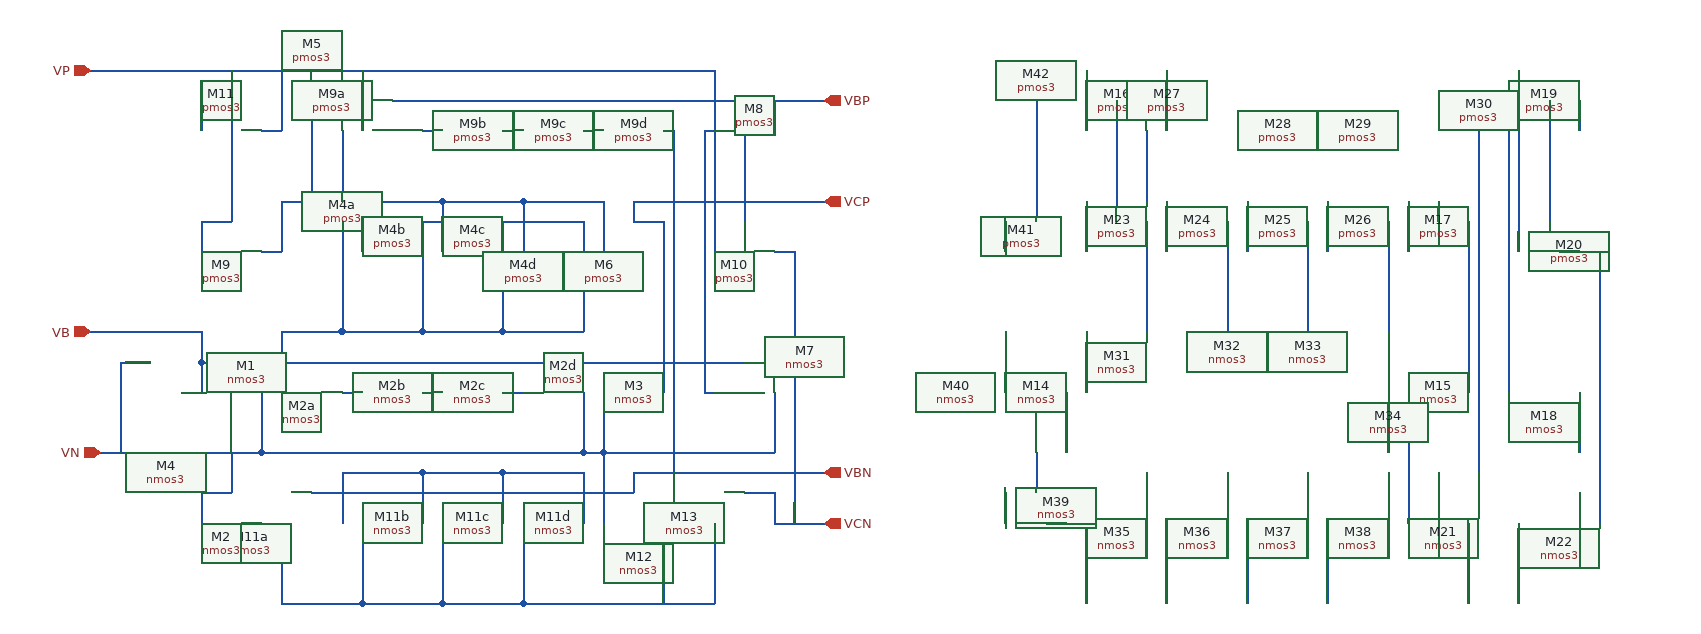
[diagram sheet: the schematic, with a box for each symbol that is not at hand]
v {xschem version=3.4.3 file_version=1.2
}
G {}
K {}
V {}
S {}
E {}
N -10 -220 -10 -170 {
lab=#net1}
N -10 -220 70 -220 {
lab=#net1}
N 70 -220 70 -170 {
lab=#net1}
N 70 -220 150 -220 {
lab=#net1}
N 150 -220 150 -170 {
lab=#net1}
N 150 -220 230 -220 {
lab=#net1}
N 230 -220 230 -170 {
lab=#net1}
N 50 -170 50 -90 {
lab=#net2}
N 50 -90 130 -90 {
lab=#net2}
N 130 -170 130 -90 {
lab=#net2}
N 130 -90 210 -90 {
lab=#net2}
N 210 -170 210 -90 {
lab=#net2}
N 210 -90 290 -90 {
lab=#net2}
N 290 -170 290 -90 {
lab=#net2}
N 20 -200 260 -200 {
lab=#net2}
N 130 -290 150 -290 {
lab=#net3}
N 210 -290 230 -290 {
lab=#net4}
N 290 -290 310 -290 {
lab=#net5}
N 100 -320 340 -320 {
lab=VBP}
N -10 -350 -10 -290 {
lab=VP}
N 20 -320 20 -200 {
lab=#net2}
N 50 -290 50 -220 {
lab=#net1}
N 310 -220 310 -170 {
lab=#net1}
N 230 -220 310 -220 {
lab=#net1}
N 50 -30 70 -30 {
lab=#net6}
N 130 -30 150 -30 {
lab=#net7}
N 210 -30 230 -30 {
lab=#net8}
N 20 -60 260 -60 {
lab=VB}
N 20 70 260 70 {
lab=VBN}
N 50 50 50 100 {
lab=#net9}
N 50 50 130 50 {
lab=#net9}
N 130 50 130 100 {
lab=#net9}
N 130 50 210 50 {
lab=#net9}
N 210 50 210 100 {
lab=#net9}
N 210 50 290 50 {
lab=#net9}
N 290 50 290 100 {
lab=#net9}
N -10 100 -10 180 {
lab=#net10}
N -10 180 70 180 {
lab=#net10}
N 70 100 70 180 {
lab=#net10}
N 70 180 150 180 {
lab=#net10}
N 150 100 150 180 {
lab=#net10}
N 150 180 230 180 {
lab=#net10}
N 230 100 230 180 {
lab=#net10}
N -90 -60 -90 -30 {
lab=VB}
N -90 -60 -60 -60 {
lab=VB}
N -60 -60 20 -60 {
lab=VB}
N 260 -60 340 -60 {
lab=VB}
N 340 -200 370 -200 {
lab=VCP}
N 370 -200 370 -170 {
lab=VCP}
N 340 -220 340 -200 {
lab=VCP}
N 340 -220 500 -220 {
lab=VCP}
N 370 -170 370 -30 {
lab=VCP}
N -10 -90 -10 -30 {
lab=#net2}
N -10 -90 50 -90 {
lab=#net2}
N 230 180 390 180 {
lab=#net10}
N 420 100 420 180 {
lab=#net10}
N -30 -30 -30 30 {
lab=VN}
N -190 30 -30 30 {
lab=VN}
N 290 -30 290 30 {
lab=VN}
N -30 30 290 30 {
lab=VN}
N 290 30 310 30 {
lab=VN}
N 310 -30 310 30 {
lab=VN}
N 310 30 390 30 {
lab=VN}
N 310 30 310 100 {
lab=VN}
N 370 100 370 180 {
lab=#net10}
N 450 70 480 70 {
lab=VCN}
N 480 70 480 100 {
lab=VCN}
N 480 100 530 100 {
lab=VCN}
N 260 70 340 70 {
lab=VBN}
N 340 50 340 70 {
lab=VBN}
N 370 -290 380 -290 {
lab=VBN}
N 380 -290 380 50 {
lab=VBN}
N 50 -200 50 -170 {
lab=#net2}
N 130 -200 130 -170 {
lab=#net2}
N 210 -200 210 -170 {
lab=#net2}
N 260 -200 290 -200 {
lab=#net2}
N 290 -200 290 -170 {
lab=#net2}
N 450 -320 450 -200 {
lab=VBP}
N 340 -320 390 -320 {
lab=VBP}
N 70 -350 70 -290 {
lab=VP}
N 420 30 480 30 {
lab=VN}
N 480 -30 480 30 {
lab=VN}
N 390 30 420 30 {
lab=VN}
N 500 -220 530 -220 {
lab=VCP}
N 450 -320 530 -320 {
lab=VBP}
N 410 -290 420 -290 {
lab=VP}
N 410 -290 410 -30 {
lab=VP}
N 410 -30 420 -30 {
lab=VP}
N 390 180 420 180 {
lab=#net10}
N 480 -320 480 -290 {
lab=VBP}
N 420 -350 420 -170 {
lab=VP}
N 390 -320 450 -320 {
lab=VBP}
N -50 -350 420 -350 {
lab=VP}
N 480 -170 500 -170 {
lab=VCN}
N 500 -170 500 100 {
lab=VCN}
N 340 50 530 50 {
lab=VBN}
N 340 -60 450 -60 {
lab=VB}
N -90 70 -90 100 {
lab=VN}
N -90 70 -60 70 {
lab=VN}
N -30 100 -10 100 {
lab=#net10}
N -60 30 -60 70 {
lab=VN}
N -110 -30 -90 -30 {
lab=VB}
N -170 -60 -140 -60 {
lab=VN}
N -170 -60 -170 -30 {
lab=VN}
N -170 -30 -170 30 {
lab=VN}
N -200 -90 -90 -90 {
lab=VB}
N -90 -90 -90 -60 {
lab=VB}
N -90 -200 -90 -170 {
lab=VP}
N -90 -200 -60 -200 {
lab=VP}
N -30 -170 -10 -170 {
lab=#net1}
N -200 -350 -50 -350 {
lab=VP}
N -30 -290 -10 -290 {}
N -90 -320 -90 -290 {}
N -90 -320 -60 -320 {}
N -60 -350 -60 -320 {}
N -60 -320 -60 -200 {}
N 790 -220 790 -170 {
lab=#net1}
N 870 -220 870 -170 {
lab=#net1}
N 950 -220 950 -170 {
lab=#net1}
N 1030 -220 1030 -170 {
lab=#net1}
N 850 -170 850 -90 {
lab=#net2}
N 930 -170 930 -90 {
lab=#net2}
N 1010 -170 1010 -90 {
lab=#net2}
N 1090 -170 1090 -90 {
lab=#net2}
N 790 -350 790 -290 {
lab=VP}
N 820 -320 820 -200 {
lab=#net2}
N 850 -290 850 -220 {
lab=#net1}
N 1110 -220 1110 -170 {
lab=#net1}
N 850 50 850 100 {
lab=#net9}
N 930 50 930 100 {
lab=#net9}
N 1010 50 1010 100 {
lab=#net9}
N 1090 50 1090 100 {
lab=#net9}
N 790 100 790 180 {
lab=#net10}
N 870 100 870 180 {
lab=#net10}
N 950 100 950 180 {
lab=#net10}
N 1030 100 1030 180 {
lab=#net10}
N 710 -60 710 -30 {
lab=VB}
N 1170 -200 1170 -170 {
lab=VCP}
N 1140 -220 1140 -200 {
lab=VCP}
N 1170 -170 1170 -30 {
lab=VCP}
N 790 -90 790 -30 {
lab=#net2}
N 1220 100 1220 180 {
lab=#net10}
N 770 -30 770 30 {
lab=VN}
N 1090 -30 1090 30 {
lab=VN}
N 1110 -30 1110 30 {
lab=VN}
N 1110 30 1110 100 {
lab=VN}
N 1170 100 1170 180 {
lab=#net10}
N 1280 70 1280 100 {
lab=VCN}
N 1140 50 1140 70 {
lab=VBN}
N 1180 -290 1180 50 {
lab=VBN}
N 850 -200 850 -170 {
lab=#net2}
N 930 -200 930 -170 {
lab=#net2}
N 1010 -200 1010 -170 {
lab=#net2}
N 1090 -200 1090 -170 {
lab=#net2}
N 1250 -320 1250 -200 {
lab=VBP}
N 870 -350 870 -290 {
lab=VP}
N 1280 -30 1280 30 {
lab=VN}
N 1210 -290 1210 -30 {
lab=VP}
N 1280 -320 1280 -290 {
lab=VBP}
N 1220 -350 1220 -170 {
lab=VP}
N 1260 -170 1280 -170 {
lab=VCN}
N 1300 -170 1300 100 {
lab=VCN}
N 710 70 710 100 {
lab=VN}
N 750 100 770 100 {
lab=#net10}
N 740 30 740 70 {
lab=VN}
N 710 -90 710 -60 {
lab=VB}
N 710 -200 710 -170 {
lab=VP}
N 740 -320 740 -200 {}
C {madvlsi/nmos3.sym} -60 -30 3 1 {name=M1
L=0.5
W=12
body=VN
nf=1
mult=1
ad="'int((nf+1)/2) * W/nf * 0.29'" 
pd="'2*int((nf+1)/2) * (W/nf + 0.29)'"
as="'int((nf+2)/2) * W/nf * 0.29'" 
ps="'2*int((nf+2)/2) * (W/nf + 0.29)'"
nrd="'0.29 / W'" nrs="'0.29 / W'"
sa=0 sb=0 sd=0
model=nfet_01v8
spiceprefix=X
}
C {madvlsi/nmos3.sym} 340 -30 1 0 {name=M3
L=0.5
W=12
body=VN
nf=1
mult=1
ad="'int((nf+1)/2) * W/nf * 0.29'" 
pd="'2*int((nf+1)/2) * (W/nf + 0.29)'"
as="'int((nf+2)/2) * W/nf * 0.29'" 
ps="'2*int((nf+2)/2) * (W/nf + 0.29)'"
nrd="'0.29 / W'" nrs="'0.29 / W'"
sa=0 sb=0 sd=0
model=nfet_01v8
spiceprefix=X
}
C {madvlsi/pmos3.sym} 20 -290 3 1 {name=M5
L=0.5
W=12
body=VP
nf=1
mult=1
ad="'int((nf+1)/2) * W/nf * 0.29'" 
pd="'2*int((nf+1)/2) * (W/nf + 0.29)'"
as="'int((nf+2)/2) * W/nf * 0.29'" 
ps="'2*int((nf+2)/2) * (W/nf + 0.29)'"
nrd="'0.29 / W'" nrs="'0.29 / W'"
sa=0 sb=0 sd=0
model=pfet_01v8
spiceprefix=X
}
C {madvlsi/pmos3.sym} 340 -170 3 1 {name=M6
L=0.5
W=12
body=VP
nf=1
mult=1
ad="'int((nf+1)/2) * W/nf * 0.29'" 
pd="'2*int((nf+1)/2) * (W/nf + 0.29)'"
as="'int((nf+2)/2) * W/nf * 0.29'" 
ps="'2*int((nf+2)/2) * (W/nf + 0.29)'"
nrd="'0.29 / W'" nrs="'0.29 / W'"
sa=0 sb=0 sd=0
model=pfet_01v8
spiceprefix=X
}
C {madvlsi/nmos3.sym} 450 -30 3 1 {name=M7
L=0.5
W=12
body=VN
nf=1
mult=1
ad="'int((nf+1)/2) * W/nf * 0.29'" 
pd="'2*int((nf+1)/2) * (W/nf + 0.29)'"
as="'int((nf+2)/2) * W/nf * 0.29'" 
ps="'2*int((nf+2)/2) * (W/nf + 0.29)'"
nrd="'0.29 / W'" nrs="'0.29 / W'"
sa=0 sb=0 sd=0
model=nfet_01v8
spiceprefix=X
}
C {madvlsi/pmos3.sym} 450 -290 3 1 {name=M8
L=0.5
W=12
body=VP
nf=1
mult=1
ad="'int((nf+1)/2) * W/nf * 0.29'" 
pd="'2*int((nf+1)/2) * (W/nf + 0.29)'"
as="'int((nf+2)/2) * W/nf * 0.29'" 
ps="'2*int((nf+2)/2) * (W/nf + 0.29)'"
nrd="'0.29 / W'" nrs="'0.29 / W'"
sa=0 sb=0 sd=0
model=pfet_01v8
spiceprefix=X
}
C {madvlsi/pmos3.sym} 450 -170 3 1 {name=M10
L=0.5
W=12
body=VP
nf=1
mult=1
ad="'int((nf+1)/2) * W/nf * 0.29'" 
pd="'2*int((nf+1)/2) * (W/nf + 0.29)'"
as="'int((nf+2)/2) * W/nf * 0.29'" 
ps="'2*int((nf+2)/2) * (W/nf + 0.29)'"
nrd="'0.29 / W'" nrs="'0.29 / W'"
sa=0 sb=0 sd=0
model=pfet_01v8
spiceprefix=X
}
C {madvlsi/nmos3.sym} 340 100 1 0 {name=M12
L=0.5
W=12
body=VN
nf=1
mult=1
ad="'int((nf+1)/2) * W/nf * 0.29'" 
pd="'2*int((nf+1)/2) * (W/nf + 0.29)'"
as="'int((nf+2)/2) * W/nf * 0.29'" 
ps="'2*int((nf+2)/2) * (W/nf + 0.29)'"
nrd="'0.29 / W'" nrs="'0.29 / W'"
sa=0 sb=0 sd=0
model=nfet_01v8
spiceprefix=X
}
C {madvlsi/nmos3.sym} 450 100 1 0 {name=M13
L=0.5
W=12
body=VN
nf=1
mult=1
ad="'int((nf+1)/2) * W/nf * 0.29'" 
pd="'2*int((nf+1)/2) * (W/nf + 0.29)'"
as="'int((nf+2)/2) * W/nf * 0.29'" 
ps="'2*int((nf+2)/2) * (W/nf + 0.29)'"
nrd="'0.29 / W'" nrs="'0.29 / W'"
sa=0 sb=0 sd=0
model=nfet_01v8
spiceprefix=X
}
C {devices/iopin.sym} -190 30 2 0 {name=p2 lab=VN}
C {devices/iopin.sym} -200 -350 2 0 {name=p3 lab=VP}
C {devices/opin.sym} 530 100 0 0 {name=p4 lab=VCN}
C {devices/opin.sym} 530 -220 0 0 {name=p5 lab=VCP}
C {devices/opin.sym} 530 -320 0 0 {name=p6 lab=VBP}
C {devices/ipin.sym} -200 -90 0 0 {name=p1 lab=VB}
C {devices/opin.sym} 530 50 0 0 {name=p7 lab=VBN}
C {madvlsi/pmos3.sym} 20 -170 3 1 {name=M4a
L=0.5
W=12
body=VP
nf=1
mult=1
ad="'int((nf+1)/2) * W/nf * 0.29'" 
pd="'2*int((nf+1)/2) * (W/nf + 0.29)'"
as="'int((nf+2)/2) * W/nf * 0.29'" 
ps="'2*int((nf+2)/2) * (W/nf + 0.29)'"
nrd="'0.29 / W'" nrs="'0.29 / W'"
sa=0 sb=0 sd=0
model=pfet_01v8
spiceprefix=X
}
C {madvlsi/pmos3.sym} 100 -170 3 1 {name=M4b
L=0.5
W=12
body=VP
nf=1
mult=1
ad="'int((nf+1)/2) * W/nf * 0.29'" 
pd="'2*int((nf+1)/2) * (W/nf + 0.29)'"
as="'int((nf+2)/2) * W/nf * 0.29'" 
ps="'2*int((nf+2)/2) * (W/nf + 0.29)'"
nrd="'0.29 / W'" nrs="'0.29 / W'"
sa=0 sb=0 sd=0
model=pfet_01v8
spiceprefix=X
}
C {madvlsi/pmos3.sym} 180 -170 3 1 {name=M4c
L=0.5
W=12
body=VP
nf=1
mult=1
ad="'int((nf+1)/2) * W/nf * 0.29'" 
pd="'2*int((nf+1)/2) * (W/nf + 0.29)'"
as="'int((nf+2)/2) * W/nf * 0.29'" 
ps="'2*int((nf+2)/2) * (W/nf + 0.29)'"
nrd="'0.29 / W'" nrs="'0.29 / W'"
sa=0 sb=0 sd=0
model=pfet_01v8
spiceprefix=X
}
C {madvlsi/pmos3.sym} 260 -170 3 1 {name=M4d
L=0.5
W=12
body=VP
nf=1
mult=1
ad="'int((nf+1)/2) * W/nf * 0.29'" 
pd="'2*int((nf+1)/2) * (W/nf + 0.29)'"
as="'int((nf+2)/2) * W/nf * 0.29'" 
ps="'2*int((nf+2)/2) * (W/nf + 0.29)'"
nrd="'0.29 / W'" nrs="'0.29 / W'"
sa=0 sb=0 sd=0
model=pfet_01v8
spiceprefix=X
}
C {madvlsi/pmos3.sym} 100 -290 3 1 {name=M9a
L=0.5
W=12
body=VP
nf=1
mult=1
ad="'int((nf+1)/2) * W/nf * 0.29'" 
pd="'2*int((nf+1)/2) * (W/nf + 0.29)'"
as="'int((nf+2)/2) * W/nf * 0.29'" 
ps="'2*int((nf+2)/2) * (W/nf + 0.29)'"
nrd="'0.29 / W'" nrs="'0.29 / W'"
sa=0 sb=0 sd=0
model=pfet_01v8
spiceprefix=X
}
C {madvlsi/pmos3.sym} 180 -290 3 1 {name=M9b
L=0.5
W=12
body=VP
nf=1
mult=1
ad="'int((nf+1)/2) * W/nf * 0.29'" 
pd="'2*int((nf+1)/2) * (W/nf + 0.29)'"
as="'int((nf+2)/2) * W/nf * 0.29'" 
ps="'2*int((nf+2)/2) * (W/nf + 0.29)'"
nrd="'0.29 / W'" nrs="'0.29 / W'"
sa=0 sb=0 sd=0
model=pfet_01v8
spiceprefix=X
}
C {madvlsi/pmos3.sym} 260 -290 3 1 {name=M9c
L=0.5
W=12
body=VP
nf=1
mult=1
ad="'int((nf+1)/2) * W/nf * 0.29'" 
pd="'2*int((nf+1)/2) * (W/nf + 0.29)'"
as="'int((nf+2)/2) * W/nf * 0.29'" 
ps="'2*int((nf+2)/2) * (W/nf + 0.29)'"
nrd="'0.29 / W'" nrs="'0.29 / W'"
sa=0 sb=0 sd=0
model=pfet_01v8
spiceprefix=X
}
C {madvlsi/pmos3.sym} 340 -290 3 1 {name=M9d
L=0.5
W=12
body=VP
nf=1
mult=1
ad="'int((nf+1)/2) * W/nf * 0.29'" 
pd="'2*int((nf+1)/2) * (W/nf + 0.29)'"
as="'int((nf+2)/2) * W/nf * 0.29'" 
ps="'2*int((nf+2)/2) * (W/nf + 0.29)'"
nrd="'0.29 / W'" nrs="'0.29 / W'"
sa=0 sb=0 sd=0
model=pfet_01v8
spiceprefix=X
}
C {madvlsi/nmos3.sym} 20 -30 3 1 {name=M2a
L=0.5
W=12
body=VN
nf=1
mult=1
ad="'int((nf+1)/2) * W/nf * 0.29'" 
pd="'2*int((nf+1)/2) * (W/nf + 0.29)'"
as="'int((nf+2)/2) * W/nf * 0.29'" 
ps="'2*int((nf+2)/2) * (W/nf + 0.29)'"
nrd="'0.29 / W'" nrs="'0.29 / W'"
sa=0 sb=0 sd=0
model=nfet_01v8
spiceprefix=X
}
C {madvlsi/nmos3.sym} 100 -30 3 1 {name=M2b
L=0.5
W=12
body=VN
nf=1
mult=1
ad="'int((nf+1)/2) * W/nf * 0.29'" 
pd="'2*int((nf+1)/2) * (W/nf + 0.29)'"
as="'int((nf+2)/2) * W/nf * 0.29'" 
ps="'2*int((nf+2)/2) * (W/nf + 0.29)'"
nrd="'0.29 / W'" nrs="'0.29 / W'"
sa=0 sb=0 sd=0
model=nfet_01v8
spiceprefix=X
}
C {madvlsi/nmos3.sym} 180 -30 3 1 {name=M2c
L=0.5
W=12
body=VN
nf=1
mult=1
ad="'int((nf+1)/2) * W/nf * 0.29'" 
pd="'2*int((nf+1)/2) * (W/nf + 0.29)'"
as="'int((nf+2)/2) * W/nf * 0.29'" 
ps="'2*int((nf+2)/2) * (W/nf + 0.29)'"
nrd="'0.29 / W'" nrs="'0.29 / W'"
sa=0 sb=0 sd=0
model=nfet_01v8
spiceprefix=X
}
C {madvlsi/nmos3.sym} 260 -30 3 1 {name=M2d
L=0.5
W=12
body=VN
nf=1
mult=1
ad="'int((nf+1)/2) * W/nf * 0.29'" 
pd="'2*int((nf+1)/2) * (W/nf + 0.29)'"
as="'int((nf+2)/2) * W/nf * 0.29'" 
ps="'2*int((nf+2)/2) * (W/nf + 0.29)'"
nrd="'0.29 / W'" nrs="'0.29 / W'"
sa=0 sb=0 sd=0
model=nfet_01v8
spiceprefix=X
}
C {madvlsi/nmos3.sym} 20 100 1 0 {name=M11a
L=0.5
W=12
body=VN
nf=1
mult=1
ad="'int((nf+1)/2) * W/nf * 0.29'" 
pd="'2*int((nf+1)/2) * (W/nf + 0.29)'"
as="'int((nf+2)/2) * W/nf * 0.29'" 
ps="'2*int((nf+2)/2) * (W/nf + 0.29)'"
nrd="'0.29 / W'" nrs="'0.29 / W'"
sa=0 sb=0 sd=0
model=nfet_01v8
spiceprefix=X
}
C {madvlsi/nmos3.sym} 100 100 1 0 {name=M11b
L=0.5
W=12
body=VN
nf=1
mult=1
ad="'int((nf+1)/2) * W/nf * 0.29'" 
pd="'2*int((nf+1)/2) * (W/nf + 0.29)'"
as="'int((nf+2)/2) * W/nf * 0.29'" 
ps="'2*int((nf+2)/2) * (W/nf + 0.29)'"
nrd="'0.29 / W'" nrs="'0.29 / W'"
sa=0 sb=0 sd=0
model=nfet_01v8
spiceprefix=X
}
C {madvlsi/nmos3.sym} 180 100 1 0 {name=M11c
L=0.5
W=12
body=VN
nf=1
mult=1
ad="'int((nf+1)/2) * W/nf * 0.29'" 
pd="'2*int((nf+1)/2) * (W/nf + 0.29)'"
as="'int((nf+2)/2) * W/nf * 0.29'" 
ps="'2*int((nf+2)/2) * (W/nf + 0.29)'"
nrd="'0.29 / W'" nrs="'0.29 / W'"
sa=0 sb=0 sd=0
model=nfet_01v8
spiceprefix=X
}
C {madvlsi/nmos3.sym} 260 100 1 0 {name=M11d
L=0.5
W=12
body=VN
nf=1
mult=1
ad="'int((nf+1)/2) * W/nf * 0.29'" 
pd="'2*int((nf+1)/2) * (W/nf + 0.29)'"
as="'int((nf+2)/2) * W/nf * 0.29'" 
ps="'2*int((nf+2)/2) * (W/nf + 0.29)'"
nrd="'0.29 / W'" nrs="'0.29 / W'"
sa=0 sb=0 sd=0
model=nfet_01v8
spiceprefix=X
}
C {madvlsi/nmos3.sym} -60 100 1 0 {name=M2
L=0.5
W=12
body=VN
nf=1
mult=1
ad="'int((nf+1)/2) * W/nf * 0.29'" 
pd="'2*int((nf+1)/2) * (W/nf + 0.29)'"
as="'int((nf+2)/2) * W/nf * 0.29'" 
ps="'2*int((nf+2)/2) * (W/nf + 0.29)'"
nrd="'0.29 / W'" nrs="'0.29 / W'"
sa=0 sb=0 sd=0
model=nfet_01v8
spiceprefix=X
}
C {madvlsi/nmos3.sym} -140 -30 1 0 {name=M4
L=0.5
W=12
body=VN
nf=1
mult=1
ad="'int((nf+1)/2) * W/nf * 0.29'" 
pd="'2*int((nf+1)/2) * (W/nf + 0.29)'"
as="'int((nf+2)/2) * W/nf * 0.29'" 
ps="'2*int((nf+2)/2) * (W/nf + 0.29)'"
nrd="'0.29 / W'" nrs="'0.29 / W'"
sa=0 sb=0 sd=0
model=nfet_01v8
spiceprefix=X
}
C {madvlsi/pmos3.sym} -60 -170 3 1 {name=M9
L=0.5
W=12
body=VP
nf=1
mult=1
ad="'int((nf+1)/2) * W/nf * 0.29'" 
pd="'2*int((nf+1)/2) * (W/nf + 0.29)'"
as="'int((nf+2)/2) * W/nf * 0.29'" 
ps="'2*int((nf+2)/2) * (W/nf + 0.29)'"
nrd="'0.29 / W'" nrs="'0.29 / W'"
sa=0 sb=0 sd=0
model=pfet_01v8
spiceprefix=X
}
C {madvlsi/pmos3.sym} -60 -290 3 1 {name=M11
L=0.5
W=12
body=VP
nf=1
mult=1
ad="'int((nf+1)/2) * W/nf * 0.29'" 
pd="'2*int((nf+1)/2) * (W/nf + 0.29)'"
as="'int((nf+2)/2) * W/nf * 0.29'" 
ps="'2*int((nf+2)/2) * (W/nf + 0.29)'"
nrd="'0.29 / W'" nrs="'0.29 / W'"
sa=0 sb=0 sd=0
model=pfet_01v8
spiceprefix=X
}
C {madvlsi/nmos3.sym} 740 -30 1 0 {name=M14
L=0.5
W=12
body=VN
nf=1
mult=1
ad="'int((nf+1)/2) * W/nf * 0.29'" 
pd="'2*int((nf+1)/2) * (W/nf + 0.29)'"
as="'int((nf+2)/2) * W/nf * 0.29'" 
ps="'2*int((nf+2)/2) * (W/nf + 0.29)'"
nrd="'0.29 / W'" nrs="'0.29 / W'"
sa=0 sb=0 sd=0
model=nfet_01v8
spiceprefix=X
}
C {madvlsi/nmos3.sym} 1140 -30 3 1 {name=M15
L=0.5
W=12
body=VN
nf=1
mult=1
ad="'int((nf+1)/2) * W/nf * 0.29'" 
pd="'2*int((nf+1)/2) * (W/nf + 0.29)'"
as="'int((nf+2)/2) * W/nf * 0.29'" 
ps="'2*int((nf+2)/2) * (W/nf + 0.29)'"
nrd="'0.29 / W'" nrs="'0.29 / W'"
sa=0 sb=0 sd=0
model=nfet_01v8
spiceprefix=X
}
C {madvlsi/pmos3.sym} 820 -290 1 0 {name=M16
L=0.5
W=12
body=VP
nf=1
mult=1
ad="'int((nf+1)/2) * W/nf * 0.29'" 
pd="'2*int((nf+1)/2) * (W/nf + 0.29)'"
as="'int((nf+2)/2) * W/nf * 0.29'" 
ps="'2*int((nf+2)/2) * (W/nf + 0.29)'"
nrd="'0.29 / W'" nrs="'0.29 / W'"
sa=0 sb=0 sd=0
model=pfet_01v8
spiceprefix=X
}
C {madvlsi/pmos3.sym} 1140 -170 1 0 {name=M17
L=0.5
W=12
body=VP
nf=1
mult=1
ad="'int((nf+1)/2) * W/nf * 0.29'" 
pd="'2*int((nf+1)/2) * (W/nf + 0.29)'"
as="'int((nf+2)/2) * W/nf * 0.29'" 
ps="'2*int((nf+2)/2) * (W/nf + 0.29)'"
nrd="'0.29 / W'" nrs="'0.29 / W'"
sa=0 sb=0 sd=0
model=pfet_01v8
spiceprefix=X
}
C {madvlsi/nmos3.sym} 1250 -30 1 0 {name=M18
L=0.5
W=12
body=VN
nf=1
mult=1
ad="'int((nf+1)/2) * W/nf * 0.29'" 
pd="'2*int((nf+1)/2) * (W/nf + 0.29)'"
as="'int((nf+2)/2) * W/nf * 0.29'" 
ps="'2*int((nf+2)/2) * (W/nf + 0.29)'"
nrd="'0.29 / W'" nrs="'0.29 / W'"
sa=0 sb=0 sd=0
model=nfet_01v8
spiceprefix=X
}
C {madvlsi/pmos3.sym} 1250 -290 1 0 {name=M19
L=0.5
W=12
body=VP
nf=1
mult=1
ad="'int((nf+1)/2) * W/nf * 0.29'" 
pd="'2*int((nf+1)/2) * (W/nf + 0.29)'"
as="'int((nf+2)/2) * W/nf * 0.29'" 
ps="'2*int((nf+2)/2) * (W/nf + 0.29)'"
nrd="'0.29 / W'" nrs="'0.29 / W'"
sa=0 sb=0 sd=0
model=pfet_01v8
spiceprefix=X
}
C {madvlsi/pmos3.sym} 1250 -170 1 0 {name=M20
L=0.5
W=12
body=VP
nf=1
mult=1
ad="'int((nf+1)/2) * W/nf * 0.29'" 
pd="'2*int((nf+1)/2) * (W/nf + 0.29)'"
as="'int((nf+2)/2) * W/nf * 0.29'" 
ps="'2*int((nf+2)/2) * (W/nf + 0.29)'"
nrd="'0.29 / W'" nrs="'0.29 / W'"
sa=0 sb=0 sd=0
model=pfet_01v8
spiceprefix=X
}
C {madvlsi/nmos3.sym} 1140 100 3 1 {name=M21
L=0.5
W=12
body=VN
nf=1
mult=1
ad="'int((nf+1)/2) * W/nf * 0.29'" 
pd="'2*int((nf+1)/2) * (W/nf + 0.29)'"
as="'int((nf+2)/2) * W/nf * 0.29'" 
ps="'2*int((nf+2)/2) * (W/nf + 0.29)'"
nrd="'0.29 / W'" nrs="'0.29 / W'"
sa=0 sb=0 sd=0
model=nfet_01v8
spiceprefix=X
}
C {madvlsi/nmos3.sym} 1250 100 3 1 {name=M22
L=0.5
W=12
body=VN
nf=1
mult=1
ad="'int((nf+1)/2) * W/nf * 0.29'" 
pd="'2*int((nf+1)/2) * (W/nf + 0.29)'"
as="'int((nf+2)/2) * W/nf * 0.29'" 
ps="'2*int((nf+2)/2) * (W/nf + 0.29)'"
nrd="'0.29 / W'" nrs="'0.29 / W'"
sa=0 sb=0 sd=0
model=nfet_01v8
spiceprefix=X
}
C {madvlsi/pmos3.sym} 820 -170 1 0 {name=M23
L=0.5
W=12
body=VP
nf=1
mult=1
ad="'int((nf+1)/2) * W/nf * 0.29'" 
pd="'2*int((nf+1)/2) * (W/nf + 0.29)'"
as="'int((nf+2)/2) * W/nf * 0.29'" 
ps="'2*int((nf+2)/2) * (W/nf + 0.29)'"
nrd="'0.29 / W'" nrs="'0.29 / W'"
sa=0 sb=0 sd=0
model=pfet_01v8
spiceprefix=X
}
C {madvlsi/pmos3.sym} 900 -170 1 0 {name=M24
L=0.5
W=12
body=VP
nf=1
mult=1
ad="'int((nf+1)/2) * W/nf * 0.29'" 
pd="'2*int((nf+1)/2) * (W/nf + 0.29)'"
as="'int((nf+2)/2) * W/nf * 0.29'" 
ps="'2*int((nf+2)/2) * (W/nf + 0.29)'"
nrd="'0.29 / W'" nrs="'0.29 / W'"
sa=0 sb=0 sd=0
model=pfet_01v8
spiceprefix=X
}
C {madvlsi/pmos3.sym} 980 -170 1 0 {name=M25
L=0.5
W=12
body=VP
nf=1
mult=1
ad="'int((nf+1)/2) * W/nf * 0.29'" 
pd="'2*int((nf+1)/2) * (W/nf + 0.29)'"
as="'int((nf+2)/2) * W/nf * 0.29'" 
ps="'2*int((nf+2)/2) * (W/nf + 0.29)'"
nrd="'0.29 / W'" nrs="'0.29 / W'"
sa=0 sb=0 sd=0
model=pfet_01v8
spiceprefix=X
}
C {madvlsi/pmos3.sym} 1060 -170 1 0 {name=M26
L=0.5
W=12
body=VP
nf=1
mult=1
ad="'int((nf+1)/2) * W/nf * 0.29'" 
pd="'2*int((nf+1)/2) * (W/nf + 0.29)'"
as="'int((nf+2)/2) * W/nf * 0.29'" 
ps="'2*int((nf+2)/2) * (W/nf + 0.29)'"
nrd="'0.29 / W'" nrs="'0.29 / W'"
sa=0 sb=0 sd=0
model=pfet_01v8
spiceprefix=X
}
C {madvlsi/pmos3.sym} 900 -290 1 0 {name=M27
L=0.5
W=12
body=VP
nf=1
mult=1
ad="'int((nf+1)/2) * W/nf * 0.29'" 
pd="'2*int((nf+1)/2) * (W/nf + 0.29)'"
as="'int((nf+2)/2) * W/nf * 0.29'" 
ps="'2*int((nf+2)/2) * (W/nf + 0.29)'"
nrd="'0.29 / W'" nrs="'0.29 / W'"
sa=0 sb=0 sd=0
model=pfet_01v8
spiceprefix=X
}
C {madvlsi/pmos3.sym} 980 -290 1 0 {name=M28
L=0.5
W=12
body=VP
nf=1
mult=1
ad="'int((nf+1)/2) * W/nf * 0.29'" 
pd="'2*int((nf+1)/2) * (W/nf + 0.29)'"
as="'int((nf+2)/2) * W/nf * 0.29'" 
ps="'2*int((nf+2)/2) * (W/nf + 0.29)'"
nrd="'0.29 / W'" nrs="'0.29 / W'"
sa=0 sb=0 sd=0
model=pfet_01v8
spiceprefix=X
}
C {madvlsi/pmos3.sym} 1060 -290 1 0 {name=M29
L=0.5
W=12
body=VP
nf=1
mult=1
ad="'int((nf+1)/2) * W/nf * 0.29'" 
pd="'2*int((nf+1)/2) * (W/nf + 0.29)'"
as="'int((nf+2)/2) * W/nf * 0.29'" 
ps="'2*int((nf+2)/2) * (W/nf + 0.29)'"
nrd="'0.29 / W'" nrs="'0.29 / W'"
sa=0 sb=0 sd=0
model=pfet_01v8
spiceprefix=X
}
C {madvlsi/pmos3.sym} 1140 -290 1 0 {name=M30
L=0.5
W=12
body=VP
nf=1
mult=1
ad="'int((nf+1)/2) * W/nf * 0.29'" 
pd="'2*int((nf+1)/2) * (W/nf + 0.29)'"
as="'int((nf+2)/2) * W/nf * 0.29'" 
ps="'2*int((nf+2)/2) * (W/nf + 0.29)'"
nrd="'0.29 / W'" nrs="'0.29 / W'"
sa=0 sb=0 sd=0
model=pfet_01v8
spiceprefix=X
}
C {madvlsi/nmos3.sym} 820 -30 1 0 {name=M31
L=0.5
W=12
body=VN
nf=1
mult=1
ad="'int((nf+1)/2) * W/nf * 0.29'" 
pd="'2*int((nf+1)/2) * (W/nf + 0.29)'"
as="'int((nf+2)/2) * W/nf * 0.29'" 
ps="'2*int((nf+2)/2) * (W/nf + 0.29)'"
nrd="'0.29 / W'" nrs="'0.29 / W'"
sa=0 sb=0 sd=0
model=nfet_01v8
spiceprefix=X
}
C {madvlsi/nmos3.sym} 900 -30 1 0 {name=M32
L=0.5
W=12
body=VN
nf=1
mult=1
ad="'int((nf+1)/2) * W/nf * 0.29'" 
pd="'2*int((nf+1)/2) * (W/nf + 0.29)'"
as="'int((nf+2)/2) * W/nf * 0.29'" 
ps="'2*int((nf+2)/2) * (W/nf + 0.29)'"
nrd="'0.29 / W'" nrs="'0.29 / W'"
sa=0 sb=0 sd=0
model=nfet_01v8
spiceprefix=X
}
C {madvlsi/nmos3.sym} 980 -30 1 0 {name=M33
L=0.5
W=12
body=VN
nf=1
mult=1
ad="'int((nf+1)/2) * W/nf * 0.29'" 
pd="'2*int((nf+1)/2) * (W/nf + 0.29)'"
as="'int((nf+2)/2) * W/nf * 0.29'" 
ps="'2*int((nf+2)/2) * (W/nf + 0.29)'"
nrd="'0.29 / W'" nrs="'0.29 / W'"
sa=0 sb=0 sd=0
model=nfet_01v8
spiceprefix=X
}
C {madvlsi/nmos3.sym} 1060 -30 1 0 {name=M34
L=0.5
W=12
body=VN
nf=1
mult=1
ad="'int((nf+1)/2) * W/nf * 0.29'" 
pd="'2*int((nf+1)/2) * (W/nf + 0.29)'"
as="'int((nf+2)/2) * W/nf * 0.29'" 
ps="'2*int((nf+2)/2) * (W/nf + 0.29)'"
nrd="'0.29 / W'" nrs="'0.29 / W'"
sa=0 sb=0 sd=0
model=nfet_01v8
spiceprefix=X
}
C {madvlsi/nmos3.sym} 820 100 3 1 {name=M35
L=0.5
W=12
body=VN
nf=1
mult=1
ad="'int((nf+1)/2) * W/nf * 0.29'" 
pd="'2*int((nf+1)/2) * (W/nf + 0.29)'"
as="'int((nf+2)/2) * W/nf * 0.29'" 
ps="'2*int((nf+2)/2) * (W/nf + 0.29)'"
nrd="'0.29 / W'" nrs="'0.29 / W'"
sa=0 sb=0 sd=0
model=nfet_01v8
spiceprefix=X
}
C {madvlsi/nmos3.sym} 900 100 3 1 {name=M36
L=0.5
W=12
body=VN
nf=1
mult=1
ad="'int((nf+1)/2) * W/nf * 0.29'" 
pd="'2*int((nf+1)/2) * (W/nf + 0.29)'"
as="'int((nf+2)/2) * W/nf * 0.29'" 
ps="'2*int((nf+2)/2) * (W/nf + 0.29)'"
nrd="'0.29 / W'" nrs="'0.29 / W'"
sa=0 sb=0 sd=0
model=nfet_01v8
spiceprefix=X
}
C {madvlsi/nmos3.sym} 980 100 3 1 {name=M37
L=0.5
W=12
body=VN
nf=1
mult=1
ad="'int((nf+1)/2) * W/nf * 0.29'" 
pd="'2*int((nf+1)/2) * (W/nf + 0.29)'"
as="'int((nf+2)/2) * W/nf * 0.29'" 
ps="'2*int((nf+2)/2) * (W/nf + 0.29)'"
nrd="'0.29 / W'" nrs="'0.29 / W'"
sa=0 sb=0 sd=0
model=nfet_01v8
spiceprefix=X
}
C {madvlsi/nmos3.sym} 1060 100 3 1 {name=M38
L=0.5
W=12
body=VN
nf=1
mult=1
ad="'int((nf+1)/2) * W/nf * 0.29'" 
pd="'2*int((nf+1)/2) * (W/nf + 0.29)'"
as="'int((nf+2)/2) * W/nf * 0.29'" 
ps="'2*int((nf+2)/2) * (W/nf + 0.29)'"
nrd="'0.29 / W'" nrs="'0.29 / W'"
sa=0 sb=0 sd=0
model=nfet_01v8
spiceprefix=X
}
C {madvlsi/nmos3.sym} 740 100 3 1 {name=M39
L=0.5
W=12
body=VN
nf=1
mult=1
ad="'int((nf+1)/2) * W/nf * 0.29'" 
pd="'2*int((nf+1)/2) * (W/nf + 0.29)'"
as="'int((nf+2)/2) * W/nf * 0.29'" 
ps="'2*int((nf+2)/2) * (W/nf + 0.29)'"
nrd="'0.29 / W'" nrs="'0.29 / W'"
sa=0 sb=0 sd=0
model=nfet_01v8
spiceprefix=X
}
C {madvlsi/nmos3.sym} 660 -30 3 1 {name=M40
L=0.5
W=12
body=VN
nf=1
mult=1
ad="'int((nf+1)/2) * W/nf * 0.29'" 
pd="'2*int((nf+1)/2) * (W/nf + 0.29)'"
as="'int((nf+2)/2) * W/nf * 0.29'" 
ps="'2*int((nf+2)/2) * (W/nf + 0.29)'"
nrd="'0.29 / W'" nrs="'0.29 / W'"
sa=0 sb=0 sd=0
model=nfet_01v8
spiceprefix=X
}
C {madvlsi/pmos3.sym} 740 -170 1 0 {name=M41
L=0.5
W=12
body=VP
nf=1
mult=1
ad="'int((nf+1)/2) * W/nf * 0.29'" 
pd="'2*int((nf+1)/2) * (W/nf + 0.29)'"
as="'int((nf+2)/2) * W/nf * 0.29'" 
ps="'2*int((nf+2)/2) * (W/nf + 0.29)'"
nrd="'0.29 / W'" nrs="'0.29 / W'"
sa=0 sb=0 sd=0
model=pfet_01v8
spiceprefix=X
}
C {madvlsi/pmos3.sym} 740 -290 1 0 {name=M42
L=0.5
W=12
body=VP
nf=1
mult=1
ad="'int((nf+1)/2) * W/nf * 0.29'" 
pd="'2*int((nf+1)/2) * (W/nf + 0.29)'"
as="'int((nf+2)/2) * W/nf * 0.29'" 
ps="'2*int((nf+2)/2) * (W/nf + 0.29)'"
nrd="'0.29 / W'" nrs="'0.29 / W'"
sa=0 sb=0 sd=0
model=pfet_01v8
spiceprefix=X
}
